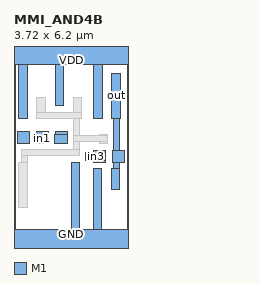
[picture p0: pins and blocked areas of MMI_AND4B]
MACRO MMI_AND4B
	CLASS CORE ;
	FOREIGN MMI_AND4B 0 0 ;
	SIZE 3.72 BY 6.2 ;
	SYMMETRY X Y ;
	SITE CORE1 ;
	PIN out
		DIRECTION output ;
		USE SIGNAL ;
		PORT
			LAYER M1 ;
			RECT 3.195 4.03 3.475 5.5 ;
			LAYER M1 ;
			RECT 3.26 2.98 3.455 4.03 ;
			LAYER M1 ;
			RECT 3.22 2.6 3.6 2.98 ;
			LAYER M1 ;
			RECT 3.26 2.4 3.455 2.6 ;
			LAYER M1 ;
			RECT 3.175 1.7 3.455 2.4 ;
		END
		AntennaDiffArea 0.91245 ;
	END out
	PIN in1
		DIRECTION input ;
		USE SIGNAL ;
		PORT
			LAYER M1 ;
			RECT 0.74 3.505 1.12 3.6 ;
			LAYER M1 ;
			RECT 0.725 3.225 1.12 3.505 ;
			LAYER M1 ;
			RECT 0.74 3.22 1.12 3.225 ;
		END
		AntennaGateArea 0.3465 ;
	END in1
	PIN GND
		DIRECTION inout ;
		USE GROUND ;
		PORT
			LAYER M1 ;
			RECT 1.86 0.42 2.14 2.605 ;
			LAYER M1 ;
			RECT 2.585 0.42 2.865 2.4 ;
			LAYER M1 ;
			RECT 0 -0.42 3.72 0.42 ;
		END
	END GND
	PIN in2
		DIRECTION input ;
		USE SIGNAL ;
		PORT
			LAYER M1 ;
			RECT 1.36 3.5 1.74 3.6 ;
			LAYER M1 ;
			RECT 1.32 3.22 1.74 3.5 ;
		END
		AntennaGateArea 0.3465 ;
	END in2
	PIN VDD
		DIRECTION inout ;
		USE POWER ;
		PORT
			LAYER M1 ;
			RECT 0 5.78 3.72 6.62 ;
			LAYER M1 ;
			RECT 0.16 4.03 0.44 5.78 ;
			LAYER M1 ;
			RECT 1.34 4.45 1.62 5.78 ;
			LAYER M1 ;
			RECT 2.605 4.03 2.885 5.78 ;
		END
	END VDD
	PIN in3
		DIRECTION input ;
		USE SIGNAL ;
		PORT
			LAYER M1 ;
			RECT 2.6 2.93 2.98 2.98 ;
			LAYER M1 ;
			RECT 2.34 2.65 2.98 2.93 ;
			LAYER M1 ;
			RECT 2.6 2.6 2.98 2.65 ;
		END
		AntennaGateArea 0.3465 ;
	END in3
	PIN in0
		DIRECTION input ;
		USE SIGNAL ;
		PORT
			LAYER M1 ;
			RECT 0.12 3.22 0.5 3.6 ;
		END
		AntennaGateArea 0.3465 ;
	END in0
	OBS
		LAYER M1 ;
		RECT 0.75 4.225 1.03 4.73 ;
		LAYER M1 ;
		RECT 1.93 4.225 2.21 4.73 ;
		LAYER M1 ;
		RECT 0.75 4.03 2.21 4.225 ;
		LAYER M1 ;
		RECT 1.94 3.465 2.135 4.03 ;
		LAYER M1 ;
		RECT 2.775 3.465 3.055 3.51 ;
		LAYER M1 ;
		RECT 1.94 3.27 3.055 3.465 ;
		LAYER M1 ;
		RECT 1.94 3.015 2.135 3.27 ;
		LAYER M1 ;
		RECT 2.775 3.23 3.055 3.27 ;
		LAYER M1 ;
		RECT 0.245 2.82 2.135 3.015 ;
		LAYER M1 ;
		RECT 0.245 2.605 0.435 2.82 ;
		LAYER M1 ;
		RECT 0.16 1.135 0.44 2.605 ;
	END
END MMI_AND4B
